VERSION 5.7 ;
  NOWIREEXTENSIONATPIN ON ;
  DIVIDERCHAR "/" ;
  BUSBITCHARS "[]" ;
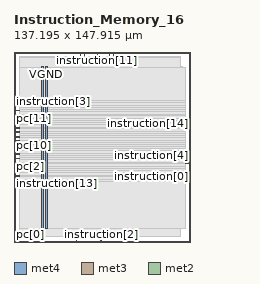
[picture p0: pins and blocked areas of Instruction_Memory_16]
MACRO Instruction_Memory_16
  CLASS BLOCK ;
  FOREIGN Instruction_Memory_16 ;
  ORIGIN 0.000 0.000 ;
  SIZE 137.195 BY 147.915 ;
  PIN VGND
    DIRECTION INOUT ;
    USE GROUND ;
    PORT
      LAYER met4 ;
        RECT 24.340 10.640 25.940 136.240 ;
    END
  END VGND
  PIN VPWR
    DIRECTION INOUT ;
    USE POWER ;
    PORT
      LAYER met4 ;
        RECT 21.040 10.640 22.640 136.240 ;
    END
  END VPWR
  PIN clk
    DIRECTION INPUT ;
    USE SIGNAL ;
    ANTENNAGATEAREA 0.852000 ;
    PORT
      LAYER met3 ;
        RECT 0.000 54.440 4.000 55.040 ;
    END
  END clk
  PIN instruction[0]
    DIRECTION OUTPUT ;
    USE SIGNAL ;
    ANTENNADIFFAREA 0.445500 ;
    PORT
      LAYER met3 ;
        RECT 133.195 51.040 137.195 51.640 ;
    END
  END instruction[0]
  PIN instruction[10]
    DIRECTION OUTPUT ;
    USE SIGNAL ;
    ANTENNADIFFAREA 0.445500 ;
    PORT
      LAYER met3 ;
        RECT 133.195 95.240 137.195 95.840 ;
    END
  END instruction[10]
  PIN instruction[11]
    DIRECTION OUTPUT ;
    USE SIGNAL ;
    ANTENNADIFFAREA 0.445500 ;
    PORT
      LAYER met2 ;
        RECT 64.490 143.915 64.770 147.915 ;
    END
  END instruction[11]
  PIN instruction[12]
    DIRECTION OUTPUT ;
    USE SIGNAL ;
    ANTENNADIFFAREA 0.445500 ;
    PORT
      LAYER met3 ;
        RECT 133.195 54.440 137.195 55.040 ;
    END
  END instruction[12]
  PIN instruction[13]
    DIRECTION OUTPUT ;
    USE SIGNAL ;
    ANTENNADIFFAREA 0.445500 ;
    PORT
      LAYER met3 ;
        RECT 0.000 51.040 4.000 51.640 ;
    END
  END instruction[13]
  PIN instruction[14]
    DIRECTION OUTPUT ;
    USE SIGNAL ;
    ANTENNADIFFAREA 0.445500 ;
    PORT
      LAYER met3 ;
        RECT 133.195 91.840 137.195 92.440 ;
    END
  END instruction[14]
  PIN instruction[15]
    DIRECTION OUTPUT ;
    USE SIGNAL ;
    ANTENNADIFFAREA 0.445500 ;
    PORT
      LAYER met2 ;
        RECT 51.610 143.915 51.890 147.915 ;
    END
  END instruction[15]
  PIN instruction[1]
    DIRECTION OUTPUT ;
    USE SIGNAL ;
    ANTENNADIFFAREA 0.445500 ;
    PORT
      LAYER met2 ;
        RECT 48.390 0.000 48.670 4.000 ;
    END
  END instruction[1]
  PIN instruction[2]
    DIRECTION OUTPUT ;
    USE SIGNAL ;
    ANTENNADIFFAREA 0.445500 ;
    PORT
      LAYER met2 ;
        RECT 67.710 0.000 67.990 4.000 ;
    END
  END instruction[2]
  PIN instruction[3]
    DIRECTION OUTPUT ;
    USE SIGNAL ;
    ANTENNADIFFAREA 0.445500 ;
    PORT
      LAYER met3 ;
        RECT 0.000 108.840 4.000 109.440 ;
    END
  END instruction[3]
  PIN instruction[4]
    DIRECTION OUTPUT ;
    USE SIGNAL ;
    ANTENNADIFFAREA 0.445500 ;
    PORT
      LAYER met3 ;
        RECT 133.195 61.240 137.195 61.840 ;
    END
  END instruction[4]
  PIN instruction[5]
    DIRECTION OUTPUT ;
    USE SIGNAL ;
    ANTENNADIFFAREA 0.445500 ;
    PORT
      LAYER met2 ;
        RECT 77.370 143.915 77.650 147.915 ;
    END
  END instruction[5]
  PIN instruction[6]
    DIRECTION OUTPUT ;
    USE SIGNAL ;
    ANTENNADIFFAREA 0.445500 ;
    PORT
      LAYER met3 ;
        RECT 133.195 88.440 137.195 89.040 ;
    END
  END instruction[6]
  PIN instruction[7]
    DIRECTION OUTPUT ;
    USE SIGNAL ;
    ANTENNADIFFAREA 0.445500 ;
    PORT
      LAYER met2 ;
        RECT 54.830 143.915 55.110 147.915 ;
    END
  END instruction[7]
  PIN instruction[8]
    DIRECTION OUTPUT ;
    USE SIGNAL ;
    ANTENNADIFFAREA 0.445500 ;
    PORT
      LAYER met3 ;
        RECT 133.195 47.640 137.195 48.240 ;
    END
  END instruction[8]
  PIN instruction[9]
    DIRECTION OUTPUT ;
    USE SIGNAL ;
    ANTENNADIFFAREA 0.445500 ;
    PORT
      LAYER met2 ;
        RECT 74.150 143.915 74.430 147.915 ;
    END
  END instruction[9]
  PIN pc[0]
    DIRECTION INPUT ;
    USE SIGNAL ;
    PORT
      LAYER met2 ;
        RECT 0.090 0.000 0.370 4.000 ;
    END
  END pc[0]
  PIN pc[10]
    DIRECTION INPUT ;
    USE SIGNAL ;
    ANTENNAGATEAREA 0.196500 ;
    PORT
      LAYER met3 ;
        RECT 0.000 74.840 4.000 75.440 ;
    END
  END pc[10]
  PIN pc[11]
    DIRECTION INPUT ;
    USE SIGNAL ;
    ANTENNAGATEAREA 0.196500 ;
    PORT
      LAYER met3 ;
        RECT 0.000 102.040 4.000 102.640 ;
    END
  END pc[11]
  PIN pc[12]
    DIRECTION INPUT ;
    USE SIGNAL ;
    ANTENNAGATEAREA 0.196500 ;
    PORT
      LAYER met3 ;
        RECT 0.000 98.640 4.000 99.240 ;
    END
  END pc[12]
  PIN pc[13]
    DIRECTION INPUT ;
    USE SIGNAL ;
    ANTENNAGATEAREA 0.196500 ;
    PORT
      LAYER met3 ;
        RECT 0.000 91.840 4.000 92.440 ;
    END
  END pc[13]
  PIN pc[14]
    DIRECTION INPUT ;
    USE SIGNAL ;
    ANTENNAGATEAREA 0.196500 ;
    PORT
      LAYER met3 ;
        RECT 0.000 88.440 4.000 89.040 ;
    END
  END pc[14]
  PIN pc[15]
    DIRECTION INPUT ;
    USE SIGNAL ;
    ANTENNAGATEAREA 0.196500 ;
    PORT
      LAYER met3 ;
        RECT 0.000 105.440 4.000 106.040 ;
    END
  END pc[15]
  PIN pc[1]
    DIRECTION INPUT ;
    USE SIGNAL ;
    ANTENNAGATEAREA 0.126000 ;
    PORT
      LAYER met3 ;
        RECT 0.000 61.240 4.000 61.840 ;
    END
  END pc[1]
  PIN pc[2]
    DIRECTION INPUT ;
    USE SIGNAL ;
    ANTENNAGATEAREA 0.213000 ;
    PORT
      LAYER met3 ;
        RECT 0.000 64.640 4.000 65.240 ;
    END
  END pc[2]
  PIN pc[3]
    DIRECTION INPUT ;
    USE SIGNAL ;
    ANTENNAGATEAREA 0.196500 ;
    PORT
      LAYER met3 ;
        RECT 0.000 57.840 4.000 58.440 ;
    END
  END pc[3]
  PIN pc[4]
    DIRECTION INPUT ;
    USE SIGNAL ;
    ANTENNAGATEAREA 0.213000 ;
    PORT
      LAYER met3 ;
        RECT 0.000 68.040 4.000 68.640 ;
    END
  END pc[4]
  PIN pc[5]
    DIRECTION INPUT ;
    USE SIGNAL ;
    ANTENNAGATEAREA 0.159000 ;
    PORT
      LAYER met3 ;
        RECT 0.000 71.440 4.000 72.040 ;
    END
  END pc[5]
  PIN pc[6]
    DIRECTION INPUT ;
    USE SIGNAL ;
    ANTENNAGATEAREA 0.196500 ;
    PORT
      LAYER met3 ;
        RECT 0.000 78.240 4.000 78.840 ;
    END
  END pc[6]
  PIN pc[7]
    DIRECTION INPUT ;
    USE SIGNAL ;
    ANTENNAGATEAREA 0.196500 ;
    PORT
      LAYER met3 ;
        RECT 0.000 85.040 4.000 85.640 ;
    END
  END pc[7]
  PIN pc[8]
    DIRECTION INPUT ;
    USE SIGNAL ;
    ANTENNAGATEAREA 0.196500 ;
    PORT
      LAYER met3 ;
        RECT 0.000 95.240 4.000 95.840 ;
    END
  END pc[8]
  PIN pc[9]
    DIRECTION INPUT ;
    USE SIGNAL ;
    ANTENNAGATEAREA 0.196500 ;
    PORT
      LAYER met3 ;
        RECT 0.000 81.640 4.000 82.240 ;
    END
  END pc[9]
  OBS
      LAYER nwell ;
        RECT 5.330 10.795 131.750 136.085 ;
      LAYER li1 ;
        RECT 5.520 10.795 131.560 136.085 ;
      LAYER met1 ;
        RECT 4.210 10.640 131.560 136.240 ;
      LAYER met2 ;
        RECT 4.230 143.635 51.330 144.570 ;
        RECT 52.170 143.635 54.550 144.570 ;
        RECT 55.390 143.635 64.210 144.570 ;
        RECT 65.050 143.635 73.870 144.570 ;
        RECT 74.710 143.635 77.090 144.570 ;
        RECT 77.930 143.635 129.630 144.570 ;
        RECT 4.230 4.280 129.630 143.635 ;
        RECT 4.230 4.000 48.110 4.280 ;
        RECT 48.950 4.000 67.430 4.280 ;
        RECT 68.270 4.000 129.630 4.280 ;
      LAYER met3 ;
        RECT 3.990 109.840 133.195 136.165 ;
        RECT 4.400 108.440 133.195 109.840 ;
        RECT 3.990 106.440 133.195 108.440 ;
        RECT 4.400 105.040 133.195 106.440 ;
        RECT 3.990 103.040 133.195 105.040 ;
        RECT 4.400 101.640 133.195 103.040 ;
        RECT 3.990 99.640 133.195 101.640 ;
        RECT 4.400 98.240 133.195 99.640 ;
        RECT 3.990 96.240 133.195 98.240 ;
        RECT 4.400 94.840 132.795 96.240 ;
        RECT 3.990 92.840 133.195 94.840 ;
        RECT 4.400 91.440 132.795 92.840 ;
        RECT 3.990 89.440 133.195 91.440 ;
        RECT 4.400 88.040 132.795 89.440 ;
        RECT 3.990 86.040 133.195 88.040 ;
        RECT 4.400 84.640 133.195 86.040 ;
        RECT 3.990 82.640 133.195 84.640 ;
        RECT 4.400 81.240 133.195 82.640 ;
        RECT 3.990 79.240 133.195 81.240 ;
        RECT 4.400 77.840 133.195 79.240 ;
        RECT 3.990 75.840 133.195 77.840 ;
        RECT 4.400 74.440 133.195 75.840 ;
        RECT 3.990 72.440 133.195 74.440 ;
        RECT 4.400 71.040 133.195 72.440 ;
        RECT 3.990 69.040 133.195 71.040 ;
        RECT 4.400 67.640 133.195 69.040 ;
        RECT 3.990 65.640 133.195 67.640 ;
        RECT 4.400 64.240 133.195 65.640 ;
        RECT 3.990 62.240 133.195 64.240 ;
        RECT 4.400 60.840 132.795 62.240 ;
        RECT 3.990 58.840 133.195 60.840 ;
        RECT 4.400 57.440 133.195 58.840 ;
        RECT 3.990 55.440 133.195 57.440 ;
        RECT 4.400 54.040 132.795 55.440 ;
        RECT 3.990 52.040 133.195 54.040 ;
        RECT 4.400 50.640 132.795 52.040 ;
        RECT 3.990 48.640 133.195 50.640 ;
        RECT 3.990 47.240 132.795 48.640 ;
        RECT 3.990 10.715 133.195 47.240 ;
  END
END Instruction_Memory_16
END LIBRARY

